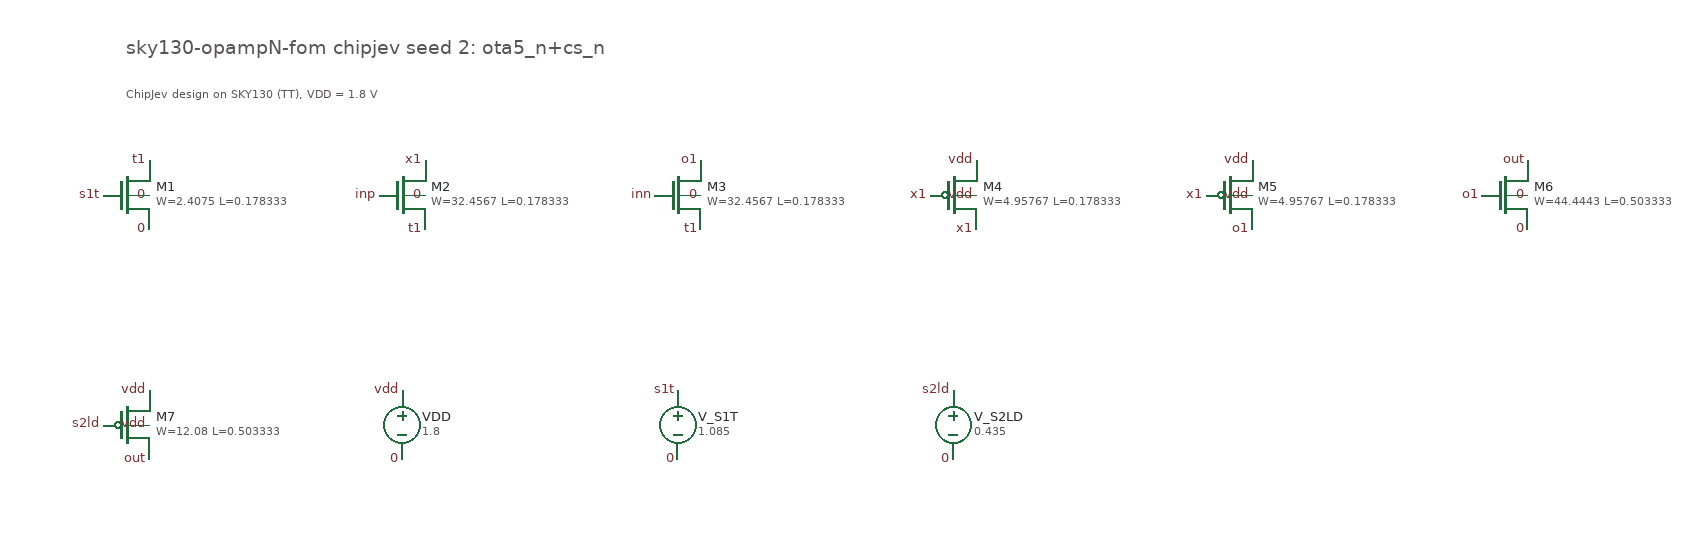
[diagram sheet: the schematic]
v {xschem version=3.4.5 file_version=1.2}
G {}
K {}
V {}
S {}
E {}
T {sky130-opampN-fom chipjev seed 2: ota5_n+cs_n} 0 -140 0 0 0.5 0.5 {}
T {ChipJev design on SKY130 (TT), VDD = 1.8 V} 0 -100 0 0 0.3 0.3 {}
C {sky130_fd_pr/nfet_01v8.sym} 0 0 0 0 {name=M1 L=0.178333 W=2.4075 nf=1 mult=1 ad=0.698175 as=0.698175 pd=5.395 ps=5.395 nrd=0.120457 nrs=0.120457 sa=0 sb=0 sd=0 model=nfet_01v8 spiceprefix=X}
C {devices/lab_pin.sym} 20 -30 0 0 {name=l1 sig_type=std_logic lab=t1}
C {devices/lab_pin.sym} -20 0 0 0 {name=l2 sig_type=std_logic lab=s1t}
C {devices/lab_pin.sym} 20 30 0 0 {name=l3 sig_type=std_logic lab=0}
C {devices/lab_pin.sym} 20 0 0 0 {name=l4 sig_type=std_logic lab=0}
C {sky130_fd_pr/nfet_01v8.sym} 240 0 0 0 {name=M2 L=0.178333 W=32.4567 nf=1 mult=1 ad=9.41243 as=9.41243 pd=65.4933 ps=65.4933 nrd=0.00893499 nrs=0.00893499 sa=0 sb=0 sd=0 model=nfet_01v8 spiceprefix=X}
C {devices/lab_pin.sym} 260 -30 0 0 {name=l5 sig_type=std_logic lab=x1}
C {devices/lab_pin.sym} 220 0 0 0 {name=l6 sig_type=std_logic lab=inp}
C {devices/lab_pin.sym} 260 30 0 0 {name=l7 sig_type=std_logic lab=t1}
C {devices/lab_pin.sym} 260 0 0 0 {name=l8 sig_type=std_logic lab=0}
C {sky130_fd_pr/nfet_01v8.sym} 480 0 0 0 {name=M3 L=0.178333 W=32.4567 nf=1 mult=1 ad=9.41243 as=9.41243 pd=65.4933 ps=65.4933 nrd=0.00893499 nrs=0.00893499 sa=0 sb=0 sd=0 model=nfet_01v8 spiceprefix=X}
C {devices/lab_pin.sym} 500 -30 0 0 {name=l9 sig_type=std_logic lab=o1}
C {devices/lab_pin.sym} 460 0 0 0 {name=l10 sig_type=std_logic lab=inn}
C {devices/lab_pin.sym} 500 30 0 0 {name=l11 sig_type=std_logic lab=t1}
C {devices/lab_pin.sym} 500 0 0 0 {name=l12 sig_type=std_logic lab=0}
C {sky130_fd_pr/pfet_01v8.sym} 720 0 0 0 {name=M4 L=0.178333 W=4.95767 nf=1 mult=1 ad=1.43772 as=1.43772 pd=10.4953 ps=10.4953 nrd=0.0584953 nrs=0.0584953 sa=0 sb=0 sd=0 model=pfet_01v8 spiceprefix=X}
C {devices/lab_pin.sym} 740 30 0 0 {name=l13 sig_type=std_logic lab=x1}
C {devices/lab_pin.sym} 700 0 0 0 {name=l14 sig_type=std_logic lab=x1}
C {devices/lab_pin.sym} 740 -30 0 0 {name=l15 sig_type=std_logic lab=vdd}
C {devices/lab_pin.sym} 740 0 0 0 {name=l16 sig_type=std_logic lab=vdd}
C {sky130_fd_pr/pfet_01v8.sym} 960 0 0 0 {name=M5 L=0.178333 W=4.95767 nf=1 mult=1 ad=1.43772 as=1.43772 pd=10.4953 ps=10.4953 nrd=0.0584953 nrs=0.0584953 sa=0 sb=0 sd=0 model=pfet_01v8 spiceprefix=X}
C {devices/lab_pin.sym} 980 30 0 0 {name=l17 sig_type=std_logic lab=o1}
C {devices/lab_pin.sym} 940 0 0 0 {name=l18 sig_type=std_logic lab=x1}
C {devices/lab_pin.sym} 980 -30 0 0 {name=l19 sig_type=std_logic lab=vdd}
C {devices/lab_pin.sym} 980 0 0 0 {name=l20 sig_type=std_logic lab=vdd}
C {sky130_fd_pr/nfet_01v8.sym} 1200 0 0 0 {name=M6 L=0.503333 W=44.4443 nf=1 mult=1 ad=12.8889 as=12.8889 pd=89.4687 ps=89.4687 nrd=0.00652502 nrs=0.00652502 sa=0 sb=0 sd=0 model=nfet_01v8 spiceprefix=X}
C {devices/lab_pin.sym} 1220 -30 0 0 {name=l21 sig_type=std_logic lab=out}
C {devices/lab_pin.sym} 1180 0 0 0 {name=l22 sig_type=std_logic lab=o1}
C {devices/lab_pin.sym} 1220 30 0 0 {name=l23 sig_type=std_logic lab=0}
C {devices/lab_pin.sym} 1220 0 0 0 {name=l24 sig_type=std_logic lab=0}
C {sky130_fd_pr/pfet_01v8.sym} 0 200 0 0 {name=M7 L=0.503333 W=12.08 nf=1 mult=1 ad=3.5032 as=3.5032 pd=24.74 ps=24.74 nrd=0.0240066 nrs=0.0240066 sa=0 sb=0 sd=0 model=pfet_01v8 spiceprefix=X}
C {devices/lab_pin.sym} 20 230 0 0 {name=l25 sig_type=std_logic lab=out}
C {devices/lab_pin.sym} -20 200 0 0 {name=l26 sig_type=std_logic lab=s2ld}
C {devices/lab_pin.sym} 20 170 0 0 {name=l27 sig_type=std_logic lab=vdd}
C {devices/lab_pin.sym} 20 200 0 0 {name=l28 sig_type=std_logic lab=vdd}
C {devices/vsource.sym} 240 200 0 0 {name=VDD value=1.8 m=1}
C {devices/lab_pin.sym} 240 170 0 0 {name=l29 sig_type=std_logic lab=vdd}
C {devices/lab_pin.sym} 240 230 0 0 {name=l30 sig_type=std_logic lab=0}
C {devices/vsource.sym} 480 200 0 0 {name=V_S1T value=1.085 m=1}
C {devices/lab_pin.sym} 480 170 0 0 {name=l31 sig_type=std_logic lab=s1t}
C {devices/lab_pin.sym} 480 230 0 0 {name=l32 sig_type=std_logic lab=0}
C {devices/vsource.sym} 720 200 0 0 {name=V_S2LD value=0.435 m=1}
C {devices/lab_pin.sym} 720 170 0 0 {name=l33 sig_type=std_logic lab=s2ld}
C {devices/lab_pin.sym} 720 230 0 0 {name=l34 sig_type=std_logic lab=0}
